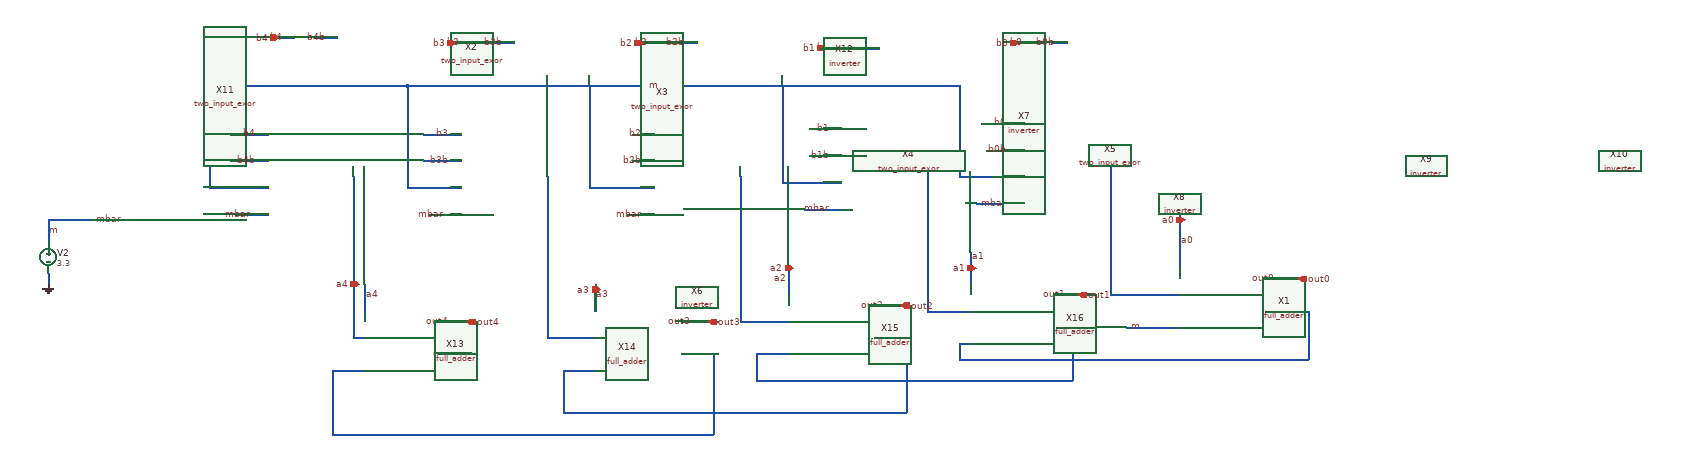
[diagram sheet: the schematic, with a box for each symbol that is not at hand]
v {xschem version=2.9.9 file_version=1.2 }
G {}
K {}
V {}
S {}
E {}
N -710 -260 -610 -260 { lab=m}
N -710 -450 -710 -260 { lab=m}
N 320 -450 320 -280 { lab=m}
N 380 -280 440 -280 { lab=m}
N -300 -260 -250 -260 { lab=m}
N -370 -450 -370 -260 { lab=m}
N 60 -270 100 -270 { lab=m}
N -10 -450 -10 -270 { lab=m}
N -1380 -100 -1380 -80 { lab=GND}
N -1380 -200 -1380 -160 { lab=m}
N -1380 -200 -1300 -200 { lab=m}
N -1260 -200 -1220 -200 { lab=mbar}
N -670 -210 -610 -210 { lab=mbar}
N -300 -210 -250 -210 { lab=mbar}
N 30 -220 100 -220 { lab=mbar}
N 350 -230 440 -230 { lab=mbar}
N -680 -360 -610 -360 { lab=b3}
N -680 -310 -610 -310 { lab=b3b}
N -290 -360 -250 -360 { lab=b2}
N -290 -310 -250 -310 { lab=b2b}
N 70 -370 100 -370 { lab=b1}
N 70 -320 100 -320 { lab=b1b}
N -370 -260 -300 -260 { lab=m}
N -10 -270 60 -270 { lab=m}
N 40 -370 70 -370 { lab=b1}
N 40 -320 70 -320 { lab=b1b}
N -710 -450 320 -450 { lab=m}
N 320 -280 390 -280 { lab=m}
N 370 -330 440 -330 { lab=b0b}
N 360 -380 440 -380 { lab=b0}
N 420 -530 450 -530 { lab=b0}
N 490 -530 520 -530 { lab=b0b}
N 130 -520 170 -520 { lab=b1b}
N 60 -520 90 -520 { lab=b1}
N -280 -530 -240 -530 { lab=b2}
N -200 -530 -170 -530 { lab=b2b}
N -630 -530 -590 -530 { lab=b3}
N -550 -530 -510 -530 { lab=b3b}
N -450 -280 -450 -10 { lab=#net1}
N -450 20 -360 20 { lab=#net1}
N -90 -280 -90 -20 { lab=#net2}
N -80 -10 0 -10 { lab=#net2}
N -360 -80 -360 -30 { lab=a3}
N 0 -110 0 -60 { lab=a2}
N 340 -140 340 -80 { lab=a1}
N 730 -210 730 -110 { lab=a0}
N 630 0 680 -0 { lab=m}
N 970 0 970 60 { lab=#net3}
N 330 60 820 60 { lab=#net3}
N 500 0 530 0 { lab=#net4}
N 530 0 530 100 { lab=#net4}
N -60 100 490 100 { lab=#net4}
N 160 20 220 20 { lab=#net5}
N -420 160 150 160 { lab=#net5}
N -420 80 -360 80 { lab=#net5}
N 160 -40 220 -40 { lab=out2}
N 500 -60 570 -60 { lab=out1}
N 890 -90 960 -90 { lab=out0}
N -420 80 -420 160 { lab=#net5}
N -450 -10 -450 20 { lab=#net1}
N 150 160 220 160 { lab=#net5}
N -60 50 -60 100 { lab=#net4}
N -60 50 -0 50 { lab=#net4}
N -90 -20 -90 -10 { lab=#net2}
N -90 -10 -80 -10 { lab=#net2}
N 220 20 220 160 { lab=#net5}
N 260 -30 340 -30 { lab=#net6}
N 260 -290 260 -30 { lab=#net6}
N 320 30 340 30 { lab=#net3}
N 320 30 320 60 { lab=#net3}
N 320 60 330 60 { lab=#net3}
N 490 100 530 100 { lab=#net4}
N 680 -0 730 -0 { lab=m}
N 600 -300 600 -60 { lab=#net7}
N 600 -60 730 -60 { lab=#net7}
N 820 60 970 60 { lab=#net3}
N 890 -30 970 -30 { lab=#net3}
N 970 -30 970 -0 { lab=#net3}
N -200 50 -140 50 { lab=#net8}
N -200 -10 -140 -10 { lab=out3}
N -1030 -210 -970 -210 { lab=mbar}
N -1040 -360 -970 -360 { lab=b4}
N -1040 -310 -970 -310 { lab=b4b}
N -960 -540 -920 -540 { lab=b4}
N -880 -540 -840 -540 { lab=b4b}
N -1080 -260 -970 -260 { lab=m}
N -1080 -450 -1080 -260 { lab=m}
N -1080 -450 -710 -450 { lab=m}
N -790 -80 -790 -30 { lab=a4}
N -650 50 -590 50 { lab=cout}
N -650 -10 -590 -10 { lab=out4}
N -810 -280 -810 -80 { lab=#net9}
N -810 -80 -810 20 { lab=#net9}
N -810 20 -790 20 { lab=#net9}
N -140 50 -140 200 { lab=#net8}
N -850 200 -140 200 { lab=#net8}
N -850 80 -850 200 { lab=#net8}
N -850 80 -790 80 { lab=#net8}
C {/home/vinodhini/Documents/two_input_exor.sym} -490 -240 0 0 {name=X2}
C {/home/vinodhini/Documents/two_input_exor.sym} -130 -240 0 0 {name=X3}
C {/home/vinodhini/Documents/two_input_exor.sym} 220 -250 0 0 {name=X4}
C {/home/vinodhini/Documents/two_input_exor.sym} 560 -260 0 0 {name=X5}
C {devices/lab_pin.sym} -240 -450 1 0 {name=l1 sig_type=std_logic lab=m}
C {devices/vsource.sym} -1380 -130 0 0 {name=V2 value=3.3}
C {devices/gnd.sym} -1380 -80 0 0 {name=l2 lab=GND}
C {devices/lab_pin.sym} -1380 -180 2 0 {name=l3 sig_type=std_logic lab=m}
C {/home/vinodhini/Documents/inverter.sym} -200 20 0 0 {name=X6}
C {devices/lab_pin.sym} -1240 -200 1 0 {name=l4 sig_type=std_logic lab=mbar}
C {devices/lab_pin.sym} -640 -210 1 0 {name=l5 sig_type=std_logic lab=mbar}
C {devices/lab_pin.sym} -270 -210 1 0 {name=l6 sig_type=std_logic lab=mbar}
C {devices/lab_pin.sym} 80 -220 1 0 {name=l7 sig_type=std_logic lab=mbar}
C {devices/lab_pin.sym} 410 -230 1 0 {name=l8 sig_type=std_logic lab=mbar}
C {devices/lab_pin.sym} 410 -380 1 0 {name=l9 sig_type=std_logic lab=b0}
C {devices/lab_pin.sym} 80 -370 1 0 {name=l10 sig_type=std_logic lab=b1}
C {devices/lab_pin.sym} -270 -360 1 0 {name=l11 sig_type=std_logic lab=b2}
C {devices/lab_pin.sym} -630 -360 1 0 {name=l12 sig_type=std_logic lab=b3}
C {/home/vinodhini/Documents/inverter.sym} 510 -310 0 0 {name=X7}
C {/home/vinodhini/Documents/inverter.sym} 860 -310 0 0 {name=X8}
C {/home/vinodhini/Documents/inverter.sym} 1190 -300 0 0 {name=X9}
C {/home/vinodhini/Documents/inverter.sym} 1550 -310 0 0 {name=X10}
C {devices/lab_pin.sym} 440 -530 1 0 {name=l13 sig_type=std_logic lab=b0}
C {devices/lab_pin.sym} 500 -530 1 0 {name=l14 sig_type=std_logic lab=b0b}
C {devices/lab_pin.sym} 410 -330 1 0 {name=l15 sig_type=std_logic lab=b0b}
C {devices/lab_pin.sym} 80 -520 1 0 {name=l16 sig_type=std_logic lab=b1}
C {devices/lab_pin.sym} 150 -520 1 0 {name=l17 sig_type=std_logic lab=b1b}
C {devices/lab_pin.sym} 80 -320 1 0 {name=l18 sig_type=std_logic lab=b1b}
C {devices/lab_pin.sym} -260 -530 1 0 {name=l19 sig_type=std_logic lab=b2}
C {devices/lab_pin.sym} -190 -530 1 0 {name=l20 sig_type=std_logic lab=b2b}
C {devices/lab_pin.sym} -270 -310 1 0 {name=l21 sig_type=std_logic lab=b2b}
C {devices/lab_pin.sym} -610 -530 1 0 {name=l22 sig_type=std_logic lab=b3}
C {devices/lab_pin.sym} -530 -530 1 0 {name=l23 sig_type=std_logic lab=b3b}
C {devices/lab_pin.sym} -630 -310 1 0 {name=l24 sig_type=std_logic lab=b3b}
C {devices/lab_pin.sym} 730 -160 2 0 {name=l25 sig_type=std_logic lab=a0}
C {devices/lab_pin.sym} 340 -130 2 0 {name=l28 sig_type=std_logic lab=a1}
C {devices/lab_pin.sym} 0 -90 0 0 {name=l29 sig_type=std_logic lab=a2}
C {devices/lab_pin.sym} -360 -60 2 0 {name=l30 sig_type=std_logic lab=a3}
C {devices/lab_pin.sym} 660 0 3 0 {name=l31 sig_type=std_logic lab=m}
C {devices/lab_pin.sym} 910 -90 1 0 {name=l32 sig_type=std_logic lab=out0}
C {devices/lab_pin.sym} 520 -60 1 0 {name=l33 sig_type=std_logic lab=out1}
C {devices/lab_pin.sym} 180 -40 1 0 {name=l34 sig_type=std_logic lab=out2}
C {devices/lab_pin.sym} -180 -10 1 0 {name=l35 sig_type=std_logic lab=out3}
C {/home/vinodhini/Documents/full_adder.sym} -220 90 0 0 {name=X14}
C {/home/vinodhini/Documents/full_adder.sym} 140 60 0 0 {name=X15}
C {/home/vinodhini/Documents/full_adder.sym} 480 40 0 0 {name=X16}
C {/home/vinodhini/Documents/full_adder.sym} 870 10 0 0 {name=X1}
C {devices/ipin.sym} 430 -530 0 0 {name=p1 lab=b0}
C {devices/ipin.sym} 70 -520 0 0 {name=p2 lab=b1}
C {devices/ipin.sym} -270 -530 0 0 {name=p3 lab=b2}
C {devices/ipin.sym} -620 -530 0 0 {name=p4 lab=b3}
C {devices/ipin.sym} 740 -200 0 0 {name=p5 lab=a0}
C {devices/ipin.sym} 350 -110 0 0 {name=p6 lab=a1}
C {devices/ipin.sym} 10 -110 0 0 {name=p7 lab=a2}
C {devices/ipin.sym} -350 -70 0 0 {name=p8 lab=a3}
C {devices/opin.sym} 950 -90 0 0 {name=p9 lab=out0}
C {devices/opin.sym} 540 -60 0 0 {name=p10 lab=out1}
C {devices/opin.sym} 210 -40 0 0 {name=p11 lab=out2}
C {devices/opin.sym} -150 -10 0 0 {name=p12 lab=out3}
C {/home/vinodhini/Documents/two_input_exor.sym} -850 -240 0 0 {name=X11}
C {devices/lab_pin.sym} -1000 -210 1 0 {name=l26 sig_type=std_logic lab=mbar}
C {devices/lab_pin.sym} -990 -360 1 0 {name=l27 sig_type=std_logic lab=b4}
C {devices/lab_pin.sym} -990 -310 1 0 {name=l37 sig_type=std_logic lab=b4b}
C {/home/vinodhini/Documents/inverter.sym} 180 -320 0 0 {name=X12}
C {devices/lab_pin.sym} -940 -540 1 0 {name=l38 sig_type=std_logic lab=b4}
C {devices/lab_pin.sym} -860 -540 1 0 {name=l39 sig_type=std_logic lab=b4b}
C {devices/ipin.sym} -950 -540 0 0 {name=p14 lab=b4}
C {devices/lab_pin.sym} -790 -60 2 0 {name=l40 sig_type=std_logic lab=a4}
C {devices/lab_pin.sym} -630 -10 1 0 {name=l41 sig_type=std_logic lab=out4}
C {devices/lab_pin.sym} -620 50 1 0 {name=l42 sig_type=std_logic lab=cout}
C {/home/vinodhini/Documents/full_adder.sym} -650 90 0 0 {name=X13}
C {devices/ipin.sym} -800 -80 2 0 {name=p15 lab=a4}
C {devices/opin.sym} -600 -10 0 0 {name=p16 lab=out4}
